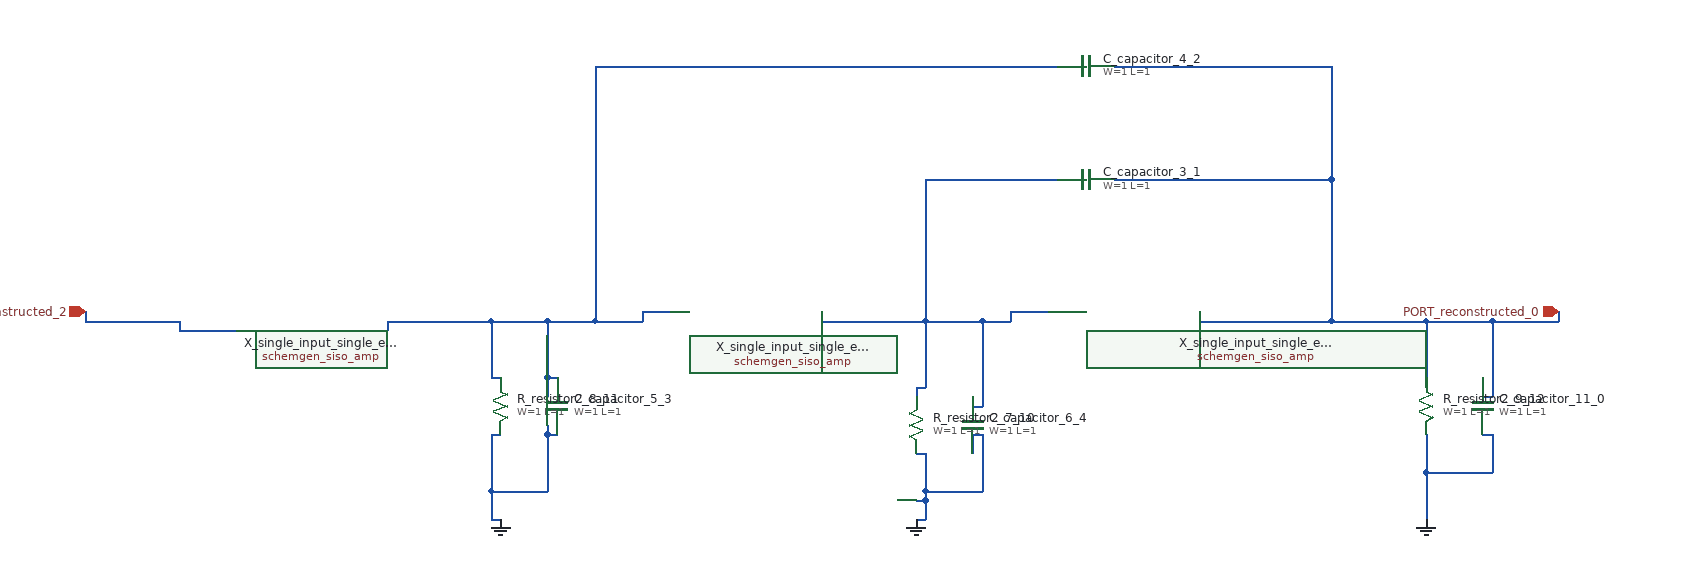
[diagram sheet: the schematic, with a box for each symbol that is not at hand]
v {xschem version=3.4.8 file_version=1.2}
G {}
K {}
V {}
S {}
E {}
C {sky130_fd_pr/cap_mim_m3_1.sym} 1540 480 2 0 {name="C_capacitor_11_0" model=cap_mim_m3_1 W=1 L=1 MF=1 spiceprefix=X}
C {sky130_fd_pr/cap_mim_m3_1.sym} 1120 240 1 0 {name="C_capacitor_3_1" model=cap_mim_m3_1 W=1 L=1 MF=1 spiceprefix=X}
C {sky130_fd_pr/cap_mim_m3_1.sym} 1120 120 1 0 {name="C_capacitor_4_2" model=cap_mim_m3_1 W=1 L=1 MF=1 spiceprefix=X}
C {sky130_fd_pr/cap_mim_m3_1.sym} 560 480 0 0 {name="C_capacitor_5_3" model=cap_mim_m3_1 W=1 L=1 MF=1 spiceprefix=X}
C {sky130_fd_pr/cap_mim_m3_1.sym} 1000 500 2 0 {name="C_capacitor_6_4" model=cap_mim_m3_1 W=1 L=1 MF=1 spiceprefix=X}
C {devices/gnd.sym} 1480 600 0 0 {name="l_gnd_10_5" lab="GND"}
C {devices/gnd.sym} 500 600 0 0 {name="l_gnd_12_6" lab="GND"}
C {devices/gnd.sym} 940 600 0 0 {name="l_gnd_13_7" lab="GND"}
C {devices/ipin.sym} 1620 380 0 0 {name="p_port_14_8" lab="PORT_reconstructed_0"}
C {devices/ipin.sym} 60 380 0 0 {name="p_port_15_9" lab="PORT_reconstructed_2"}
C {sky130_fd_pr/res_generic_po.sym} 940 500 2 0 {name="R_resistor2_7_10"
W=1
L=1
model=res_generic_po
spiceprefix=X
mult=1}
C {sky130_fd_pr/res_generic_po.sym} 500 480 0 0 {name="R_resistor2_8_11"
W=1
L=1
model=res_generic_po
spiceprefix=X
mult=1}
C {sky130_fd_pr/res_generic_po.sym} 1480 480 0 0 {name="R_resistor2_9_12"
W=1
L=1
model=res_generic_po
spiceprefix=X
mult=1}
C {schemgen_siso_amp.sym} 1160 380 0 0 {name="X_single_input_single_end_amp_0_13"}
C {schemgen_siso_amp.sym} 760 380 0 0 {name="X_single_input_single_end_amp_1_14"}
C {schemgen_siso_amp.sym} 300 400 0 0 {name="X_single_input_single_end_amp_2_15"}
N 1540 470 1550 470 {}
N 1240 390 1380 390 {}
N 1380 390 1480 390 {}
N 1480 390 1550 390 {}
N 1550 390 1620 390 {}
N 1150 240 1380 240 {}
N 1150 120 1380 120 {}
N 1240 390 1240 380 {}
N 1380 390 1380 240 {}
N 1380 240 1380 120 {}
N 1480 460 1480 450 {}
N 1480 450 1480 390 {}
N 1540 470 1540 450 {}
N 1550 470 1550 390 {}
N 1620 390 1620 380 {}
N 490 600 500 600 {}
N 940 600 950 600 {}
N 940 580 950 580 {}
N 490 570 550 570 {}
N 950 570 1010 570 {}
N 1480 550 1550 550 {}
N 940 530 950 530 {}
N 490 510 500 510 {}
N 550 510 560 510 {}
N 1000 510 1010 510 {}
N 1540 510 1550 510 {}
N 490 600 490 570 {}
N 490 570 490 510 {}
N 550 570 550 510 {}
N 550 510 550 500 {}
N 950 600 950 580 {}
N 950 580 950 570 {}
N 950 570 950 530 {}
N 1000 530 1000 510 {}
N 1010 570 1010 510 {}
N 1480 600 1480 550 {}
N 1480 550 1480 510 {}
N 1550 550 1550 510 {}
N 160 400 220 400 {}
N 60 390 160 390 {}
N 60 390 60 380 {}
N 160 400 160 390 {}
N 1000 480 1010 480 {}
N 940 460 950 460 {}
N 840 390 950 390 {}
N 950 390 1010 390 {}
N 1010 390 1040 390 {}
N 1040 380 1080 380 {}
N 950 240 1090 240 {}
N 1090 240 1100 240 {}
N 840 390 840 380 {}
N 940 470 940 460 {}
N 950 460 950 390 {}
N 950 390 950 240 {}
N 1000 480 1000 470 {}
N 1010 480 1010 390 {}
N 1040 390 1040 380 {}
N 490 450 500 450 {}
N 550 450 560 450 {}
N 380 390 490 390 {}
N 490 390 550 390 {}
N 550 390 600 390 {}
N 600 390 650 390 {}
N 650 380 680 380 {}
N 600 120 1090 120 {}
N 1090 120 1100 120 {}
N 380 400 380 390 {}
N 490 450 490 390 {}
N 550 470 550 450 {}
N 550 450 550 390 {}
N 600 390 600 120 {}
N 650 390 650 380 {}
